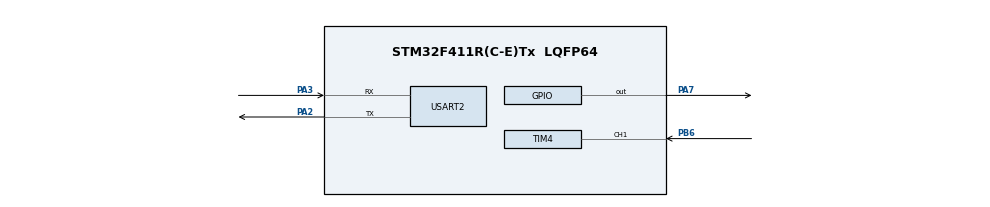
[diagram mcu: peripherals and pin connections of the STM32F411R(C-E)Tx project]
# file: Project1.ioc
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Mcu.Family=STM32F4
Mcu.Name=STM32F411R(C-E)Tx
Mcu.Package=LQFP64
NVIC.PriorityGroup=NVIC_PRIORITYGROUP_4
PA2.Mode=Asynchronous
PA2.Signal=USART2_TX
PA3.Mode=Asynchronous
PA3.Signal=USART2_RX
PA7.Signal=GPIO_Output
PB6.Signal=S_TIM4_CH1
PH0\ -\ OSC_IN.Mode=HSE-External-Oscillator
PH0\ -\ OSC_IN.Signal=RCC_OSC_IN
PH1\ -\ OSC_OUT.Mode=HSE-External-Oscillator
PH1\ -\ OSC_OUT.Signal=RCC_OSC_OUT
ProjectManager.HeapSize=0x200
ProjectManager.StackSize=0x400
ProjectManager.TargetToolchain=STM32CubeIDE
RCC.48MHZClocksFreq_Value=42000000
RCC.AHBFreq_Value=84000000
RCC.APB1CLKDivider=RCC_HCLK_DIV2
RCC.APB1Freq_Value=42000000
RCC.APB1TimFreq_Value=84000000
RCC.APB2Freq_Value=84000000
RCC.APB2TimFreq_Value=84000000
RCC.CortexFreq_Value=84000000
RCC.HCLKFreq_Value=84000000
RCC.HSE_VALUE=25000000
RCC.HSI_VALUE=16000000
RCC.LSE_VALUE=32768
RCC.PLLM=25
RCC.PLLN=168
RCC.PLLSourceVirtual=RCC_PLLSOURCE_HSE
RCC.SYSCLKFreq_VALUE=84000000
RCC.SYSCLKSource=RCC_SYSCLKSOURCE_PLLCLK
RCC.VCOOutputFreq_Value=168000000
SH.S_TIM4_CH1.0=TIM4_CH1,Input_Capture1_from_TI1
TIM3.Prescaler=84-1
TIM4.Channel-Input_Capture1_from_TI1=TIM_CHANNEL_1
TIM4.Prescaler=84-1
USART2.VirtualMode=VM_ASYNC
VP_TIM3_VS_ClockSourceINT.Mode=Internal
VP_TIM4_VS_ClockSourceINT.Mode=Internal
board=custom

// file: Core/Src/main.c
/* USER CODE BEGIN Header */
/**
  ******************************************************************************
  * @file           : main.c
  * @brief          : Main program body
  ******************************************************************************
  * @attention
  *
  * Copyright (c) 2025 STMicroelectronics.
  * All rights reserved.
  *
  * This software is licensed under terms that can be found in the LICENSE file
  * in the root directory of this software component.
  * If no LICENSE file comes with this software, it is provided AS-IS.
  *
  ******************************************************************************
  */
/* USER CODE END Header */
#include "main.h"
#include <stdio.h>

TIM_HandleTypeDef htim3;
TIM_HandleTypeDef htim4;
UART_HandleTypeDef huart2;

uint32_t distance = 0;
uint32_t width = 0;
uint16_t UEV_count = 0;

uint32_t start_captured = 0;
uint32_t first_captured = 0;
uint8_t first_captured_flag = 0;
uint32_t second_captured = 0;
uint8_t flag1 = 0;
uint8_t flag2 = 0;

void SystemClock_Config(void);
static void MX_GPIO_Init(void);
static void MX_TIM3_Init(void);
static void MX_USART2_UART_Init(void);
static void MX_TIM4_Init(void);

double Get_Distance(void);
void Make_Ultrawave_Pulse(void);

int main(void)
{
  HAL_Init();
  SystemClock_Config();
  MX_GPIO_Init();
  MX_USART2_UART_Init();
	MX_TIM3_Init();
  MX_TIM4_Init();

	flag1 = 1;
  while (1)
  {
		if (flag1)
			Make_Ultrawave_Pulse();
		else if (flag2)
		{
			char buffer[20];
			int len;

			if (width >= 36000)
				len = sprintf(buffer, "%lu cm\r\n", (unsigned long)0);
			else
				len = sprintf(buffer, "%lu cm\r\n", (unsigned long)distance);

			HAL_UART_Transmit(&huart2, (uint8_t*)buffer, len, HAL_MAX_DELAY);

			// Wait till TIM3 UEV and TIM4 CCR counts over 10ms
			while(__HAL_TIM_GET_COUNTER(&htim3) < 60000-1);
			while(__HAL_TIM_GET_COUNTER(&htim4) < 10000-1);

			__HAL_TIM_SET_COUNTER(&htim3, 0);
			// HAL_TIM_Base_Stop(&htim3);
			__HAL_TIM_SET_COUNTER(&htim4, 0);
			// HAL_TIM_Base_Stop(&htim4);

			flag1 = 1;
			flag2 = 0;

		}
	}
}

void Make_Ultrawave_Pulse(void)
{
		// Generate 10uS Pulse
    HAL_TIM_Base_Start(&htim3);
    HAL_GPIO_WritePin(GPIOA, GPIO_PIN_7, GPIO_PIN_SET);
    __HAL_TIM_SET_COUNTER(&htim3, 0);
    while (__HAL_TIM_GET_COUNTER(&htim3) < 10);		// delay 10uS
		HAL_GPIO_WritePin(GPIOA, GPIO_PIN_7, GPIO_PIN_RESET);

		__HAL_TIM_SET_COUNTER(&htim3, 0);

		// Start TIM4
		HAL_TIM_Base_Start(&htim4);
    __HAL_TIM_ENABLE_IT(&htim4, TIM_IT_CC1);
    HAL_TIM_IC_Start_IT(&htim4, TIM_CHANNEL_1);

		flag1 = 0;
}

void HAL_TIM_IC_CaptureCallback(TIM_HandleTypeDef *htim)
{
	if (htim->Channel == HAL_TIM_ACTIVE_CHANNEL_1)
	{
		if (first_captured_flag == 0)
		{
			first_captured = HAL_TIM_ReadCapturedValue(htim, TIM_CHANNEL_1);	//CCR1 register
			__HAL_TIM_SET_CAPTUREPOLARITY(htim, TIM_CHANNEL_1, TIM_INPUTCHANNELPOLARITY_FALLING);
			first_captured_flag = 1;
		}
		else
		{
			second_captured = HAL_TIM_ReadCapturedValue(htim, TIM_CHANNEL_1);
			__HAL_TIM_SET_CAPTUREPOLARITY(htim, TIM_CHANNEL_1, TIM_INPUTCHANNELPOLARITY_RISING);
			__HAL_TIM_SET_COUNTER(htim, 0);

			if (first_captured > second_captured)
				width = 0xffff + second_captured - first_captured;
			else
				width = second_captured - first_captured;

			distance = width / 58;

			__HAL_TIM_DISABLE_IT(&htim4, TIM_IT_CC1);
			first_captured_flag = 0;
			flag2 = 1;
		}

	}
}

void SystemClock_Config(void)
{
  RCC_OscInitTypeDef RCC_OscInitStruct = {0};
  RCC_ClkInitTypeDef RCC_ClkInitStruct = {0};

  /** Initializes the RCC Oscillators according to the specified parameters
  * in the RCC_OscInitTypeDef structure.
  */
  RCC_OscInitStruct.OscillatorType = RCC_OSCILLATORTYPE_HSI;
  RCC_OscInitStruct.HSIState = RCC_HSI_ON;
  RCC_OscInitStruct.HSICalibrationValue = RCC_HSICALIBRATION_DEFAULT;
  RCC_OscInitStruct.PLL.PLLState = RCC_PLL_ON;
  RCC_OscInitStruct.PLL.PLLSource = RCC_PLLSOURCE_HSI_DIV2;
  RCC_OscInitStruct.PLL.PLLMUL = RCC_PLL_MUL16;
  if (HAL_RCC_OscConfig(&RCC_OscInitStruct) != HAL_OK)
  {
    Error_Handler();
  }

  /** Initializes the CPU, AHB and APB buses clocks
  */
  RCC_ClkInitStruct.ClockType = RCC_CLOCKTYPE_HCLK|RCC_CLOCKTYPE_SYSCLK
                              |RCC_CLOCKTYPE_PCLK1|RCC_CLOCKTYPE_PCLK2;
  RCC_ClkInitStruct.SYSCLKSource = RCC_SYSCLKSOURCE_PLLCLK;
  RCC_ClkInitStruct.AHBCLKDivider = RCC_SYSCLK_DIV1;
  RCC_ClkInitStruct.APB1CLKDivider = RCC_HCLK_DIV2;
  RCC_ClkInitStruct.APB2CLKDivider = RCC_HCLK_DIV1;

  if (HAL_RCC_ClockConfig(&RCC_ClkInitStruct, FLASH_LATENCY_2) != HAL_OK)
  {
    Error_Handler();
  }
}

static void MX_TIM3_Init(void)
{

  TIM_ClockConfigTypeDef sClockSourceConfig = {0};
  TIM_MasterConfigTypeDef sMasterConfig = {0};
  TIM_OC_InitTypeDef sConfigOC = {0};

  htim3.Instance = TIM3;
  htim3.Init.Prescaler = 64-1;
  htim3.Init.CounterMode = TIM_COUNTERMODE_UP;
  htim3.Init.Period = 60000-1;
  htim3.Init.ClockDivision = TIM_CLOCKDIVISION_DIV1;
  htim3.Init.AutoReloadPreload = TIM_AUTORELOAD_PRELOAD_DISABLE;
  if (HAL_TIM_Base_Init(&htim3) != HAL_OK)
  {
    Error_Handler();
  }
  sClockSourceConfig.ClockSource = TIM_CLOCKSOURCE_INTERNAL;
  if (HAL_TIM_ConfigClockSource(&htim3, &sClockSourceConfig) != HAL_OK)
  {
    Error_Handler();
  }
  if (HAL_TIM_OC_Init(&htim3) != HAL_OK)
  {
    Error_Handler();
  }
  sMasterConfig.MasterOutputTrigger = TIM_TRGO_RESET;
  sMasterConfig.MasterSlaveMode = TIM_MASTERSLAVEMODE_DISABLE;
  if (HAL_TIMEx_MasterConfigSynchronization(&htim3, &sMasterConfig) != HAL_OK)
  {
    Error_Handler();
  }
  sConfigOC.OCMode = TIM_OCMODE_TIMING;
  sConfigOC.Pulse = 10-1;
  sConfigOC.OCPolarity = TIM_OCPOLARITY_HIGH;
  sConfigOC.OCFastMode = TIM_OCFAST_DISABLE;
  if (HAL_TIM_OC_ConfigChannel(&htim3, &sConfigOC, TIM_CHANNEL_1) != HAL_OK)
  {
    Error_Handler();
  }
  __HAL_TIM_ENABLE_OCxPRELOAD(&htim3, TIM_CHANNEL_1);

}

static void MX_TIM4_Init(void)
{

  TIM_ClockConfigTypeDef sClockSourceConfig = {0};
  TIM_MasterConfigTypeDef sMasterConfig = {0};
  TIM_IC_InitTypeDef sConfigIC = {0};

  htim4.Instance = TIM4;
  htim4.Init.Prescaler = 64-1;
  htim4.Init.CounterMode = TIM_COUNTERMODE_UP;
  htim4.Init.Period = 65536-1;
  htim4.Init.ClockDivision = TIM_CLOCKDIVISION_DIV1;
  htim4.Init.AutoReloadPreload = TIM_AUTORELOAD_PRELOAD_DISABLE;
  if (HAL_TIM_Base_Init(&htim4) != HAL_OK)
  {
    Error_Handler();
  }
  sClockSourceConfig.ClockSource = TIM_CLOCKSOURCE_INTERNAL;
  if (HAL_TIM_ConfigClockSource(&htim4, &sClockSourceConfig) != HAL_OK)
  {
    Error_Handler();
  }
  if (HAL_TIM_IC_Init(&htim4) != HAL_OK)
  {
    Error_Handler();
  }
  sMasterConfig.MasterOutputTrigger = TIM_TRGO_RESET;
  sMasterConfig.MasterSlaveMode = TIM_MASTERSLAVEMODE_DISABLE;
  if (HAL_TIMEx_MasterConfigSynchronization(&htim4, &sMasterConfig) != HAL_OK)
  {
    Error_Handler();
  }
  sConfigIC.ICPolarity = TIM_INPUTCHANNELPOLARITY_RISING;
  sConfigIC.ICSelection = TIM_ICSELECTION_DIRECTTI;
  sConfigIC.ICPrescaler = TIM_ICPSC_DIV1;
  sConfigIC.ICFilter = 0;
  if (HAL_TIM_IC_ConfigChannel(&htim4, &sConfigIC, TIM_CHANNEL_1) != HAL_OK)
  {
    Error_Handler();
  }
  /* USER CODE BEGIN TIM4_Init 2 */
	/*

	5. HAL_TIM_IC_Start(), HAL_TIM_IC_Start_DMA(), HAL_TIM_IC_Start_IT()
	6. HAL_TIM_DMABurst_WriteStart(), HAL_TIM_DMABurst_ReadStart()

	*/
  /* USER CODE END TIM4_Init 2 */

}

static void MX_USART2_UART_Init(void)
{

  huart2.Instance = USART2;
  huart2.Init.BaudRate = 9600;
  huart2.Init.WordLength = UART_WORDLENGTH_8B;
  huart2.Init.StopBits = UART_STOPBITS_1;
  huart2.Init.Parity = UART_PARITY_NONE;
  huart2.Init.Mode = UART_MODE_TX_RX;
  huart2.Init.HwFlowCtl = UART_HWCONTROL_NONE;
  huart2.Init.OverSampling = UART_OVERSAMPLING_16;
  if (HAL_UART_Init(&huart2) != HAL_OK)
  {
    Error_Handler();
  }

}

static void MX_GPIO_Init(void)
{
  GPIO_InitTypeDef GPIO_InitStruct = {0};

  /* GPIO Ports Clock Enable */
  __HAL_RCC_GPIOC_CLK_ENABLE();
  __HAL_RCC_GPIOA_CLK_ENABLE();
  __HAL_RCC_GPIOB_CLK_ENABLE();

  /*Configure GPIO pin Output Level */
  HAL_GPIO_WritePin(GPIOC, GPIO_PIN_0|GPIO_PIN_1|GPIO_PIN_2|GPIO_PIN_3
                          |GPIO_PIN_4|GPIO_PIN_5|GPIO_PIN_6|GPIO_PIN_7, GPIO_PIN_RESET);

  /*Configure GPIO pin Output Level */
  HAL_GPIO_WritePin(GPIOA, LD2_Pin|Trig_Pin_Pin, GPIO_PIN_RESET);

  /*Configure GPIO pin : B1_Pin */
  GPIO_InitStruct.Pin = B1_Pin;
  GPIO_InitStruct.Mode = GPIO_MODE_IT_RISING;
  GPIO_InitStruct.Pull = GPIO_NOPULL;
  HAL_GPIO_Init(B1_GPIO_Port, &GPIO_InitStruct);

  /*Configure GPIO pins : PC0 PC1 PC2 PC3
                           PC4 PC5 PC6 PC7 */
  GPIO_InitStruct.Pin = GPIO_PIN_0|GPIO_PIN_1|GPIO_PIN_2|GPIO_PIN_3
                          |GPIO_PIN_4|GPIO_PIN_5|GPIO_PIN_6|GPIO_PIN_7;
  GPIO_InitStruct.Mode = GPIO_MODE_OUTPUT_PP;
  GPIO_InitStruct.Pull = GPIO_NOPULL;
  GPIO_InitStruct.Speed = GPIO_SPEED_FREQ_LOW;
  HAL_GPIO_Init(GPIOC, &GPIO_InitStruct);

  /*Configure GPIO pins : LD2_Pin Trig_Pin_Pin */
  GPIO_InitStruct.Pin = LD2_Pin|Trig_Pin_Pin;
  GPIO_InitStruct.Mode = GPIO_MODE_OUTPUT_PP;
  GPIO_InitStruct.Pull = GPIO_NOPULL;
  GPIO_InitStruct.Speed = GPIO_SPEED_FREQ_LOW;
  HAL_GPIO_Init(GPIOA, &GPIO_InitStruct);

  /*Configure GPIO pins : SW4_Pin SW2_Pin SW3_Pin */
  GPIO_InitStruct.Pin = SW4_Pin|SW2_Pin|SW3_Pin;
  GPIO_InitStruct.Mode = GPIO_MODE_IT_RISING;
  GPIO_InitStruct.Pull = GPIO_NOPULL;
  HAL_GPIO_Init(GPIOB, &GPIO_InitStruct);

  /*Configure GPIO pin : SW1_Pin */
  GPIO_InitStruct.Pin = SW1_Pin;
  GPIO_InitStruct.Mode = GPIO_MODE_IT_RISING;
  GPIO_InitStruct.Pull = GPIO_NOPULL;
  HAL_GPIO_Init(SW1_GPIO_Port, &GPIO_InitStruct);

  /* EXTI interrupt init*/
  HAL_NVIC_SetPriority(EXTI4_IRQn, 0, 0);
  HAL_NVIC_EnableIRQ(EXTI4_IRQn);

  HAL_NVIC_SetPriority(EXTI9_5_IRQn, 0, 0);
  HAL_NVIC_EnableIRQ(EXTI9_5_IRQn);

  HAL_NVIC_SetPriority(EXTI15_10_IRQn, 0, 0);
  HAL_NVIC_EnableIRQ(EXTI15_10_IRQn);

}

void Error_Handler(void)
{
}
